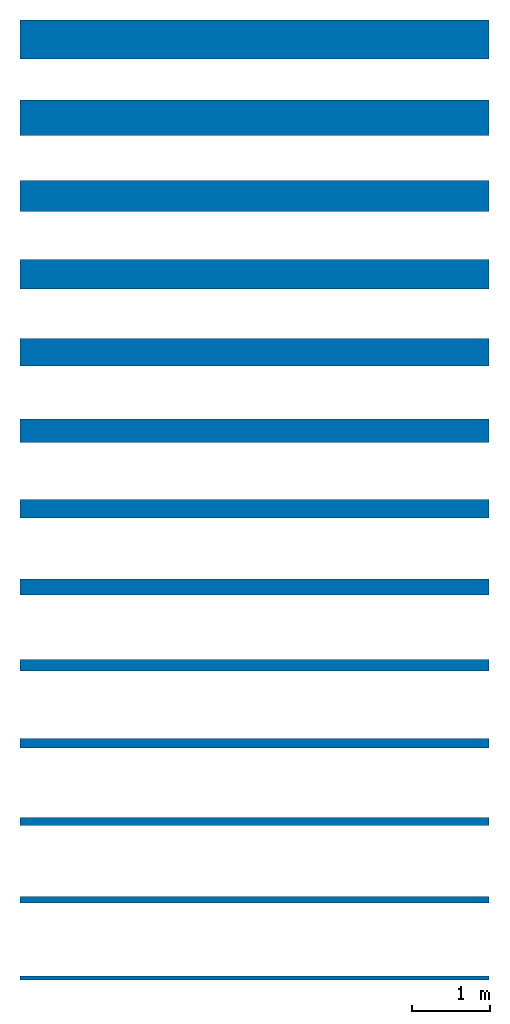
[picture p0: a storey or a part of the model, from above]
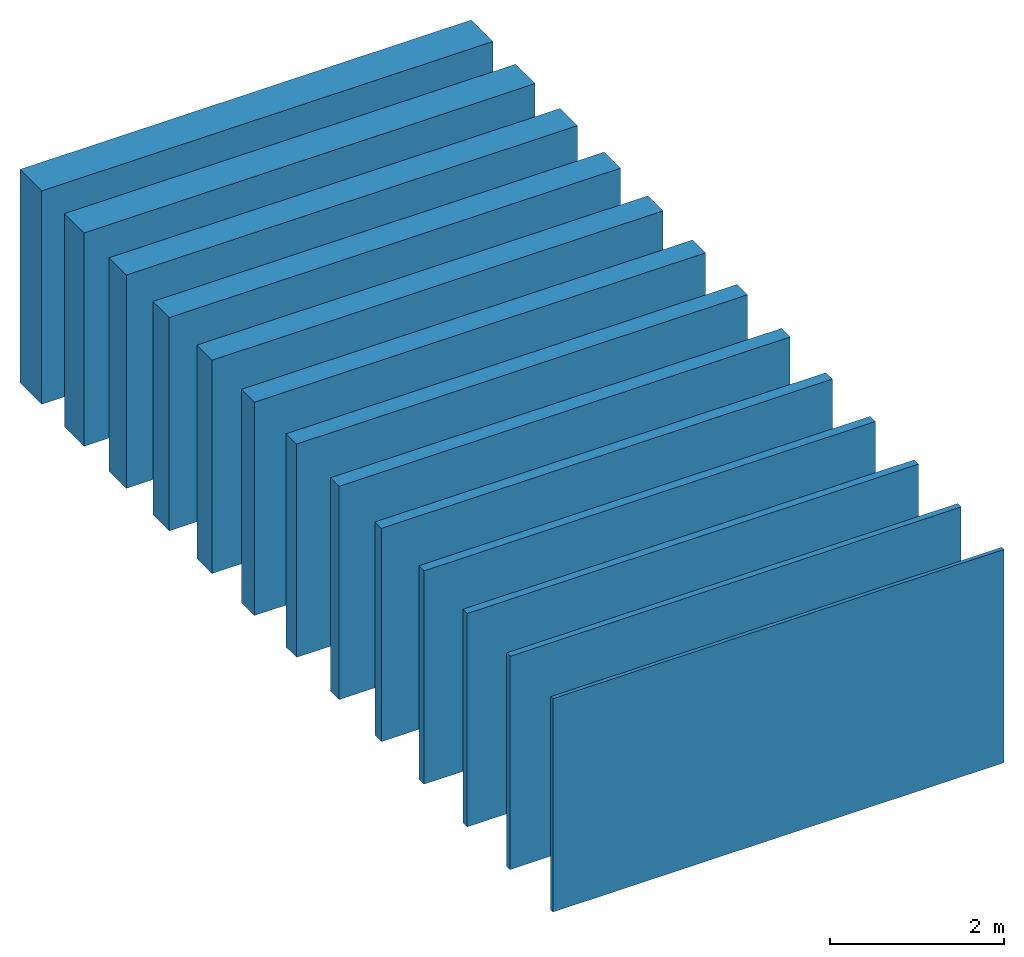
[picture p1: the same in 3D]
Properties of the parts of a building model (IFC2X3)

# File
Description: ViewDefinition [CoordinationView]
File name: Numero
Time: 2019-05-03T09:53:45
Written by: The EXPRESS Data Manager Version 5.02.0100.07 : 28 Aug 2013
Made in: 20150220_1215(x64) - Exporter 16.0.428.0 - Default UI
Comment: STEP Physical File produced by: The EXPRESS Data Manager Version 5.02.0100.07 : 28 Aug 2013 * Module: EDMstepFileFactory/EDMstandAlone * Creation date: Fri May 03 09:53:45 2019 * Host: HP-RS * Database: C:\Users\EKORU_~1\AppData\Local\Temp\{117FAC86-BFD7-4552-8663-6DD27C934700}\ifc * Database version: 5507 * Database creation date: Fri May 03 09:53:45 2019 * Schema: IFC2X3 * Model: DataRepository.ifc * Model creation date: Fri May 03 09:53:45 2019 * Header model: DataRepository.ifc_HeaderModel * Header model creation date: Fri May 03 09:53:45 2019 * EDMuser: sdai-user * EDMgroup: sdai-group * License ID and type: 5605 : Permanent license. Expiry date: * EDMstepFileFactory options: 020000

# IfcProject, Numero
LongName: Nome; Phase: Stato

# IfcSite, Default
RefLatitude: 41, 47, 59, 999999; RefLongitude: 12, 35, 59, 999999; RefElevation: 0 mm
Altro - Categoria: Informazioni sul progetto; Data di consegna del progetto: Data; Indirizzo del progetto: Immettere l'indirizzo; Nome del cliente: Proprietario; Nome del progetto: Nome; Numero del progetto: Numero; Stato del progetto: Stato

# IfcBuilding
Pset_BuildingCommon - NumberOfStoreys: 1
Altro - Categoria: Informazioni sul progetto; Data di consegna del progetto: Data; Indirizzo del progetto: Immettere l'indirizzo; Nome del cliente: Proprietario; Nome del progetto: Nome; Numero del progetto: Numero; Stato del progetto: Stato

# IfcBuildingStorey, Livello 1
LongName: Livello 1; Elevation: 0 mm
Vincoli - Base quota altimetrica: Punto base progetto; Quota altimetrica: 0 mm
Altro - Categoria: Livelli; Famiglia: Livello: Estremità 8 mm; Famiglia e tipo: Livello: Estremità 8 mm; ID tipo: Livello: Estremità 8 mm; Tipo: Livello: Estremità 8 mm; Nome famiglia: Livello
Dati identità - Strutturale: no; Nome: Livello 1; Piano edificio: yes; Nome del tipo: Estremità 8 mm
Dimensioni - Altezza di calcolo: 0 mm
Grafica - Colore: 0; Modello di linea: Centro; Simbolo: Estremità del livello - Cerchio: Estremità del livello - Cerchio; Simbolo a estremità 1 per default: no; Simbolo a estremità 2 per default: yes; Spessore di linea: 1

# IfcWallStandardCase: Muro di base:GASBETON Evolution sp. 100 mm, Muro di base:GASBETON Evolution sp. 100 mm:129163
In: Livello 1
Type - PredefinedType: STANDARD; Material: GASBETON Evolution 100 mm
Type - Altro - Categoria: Muri; Nome famiglia: Muro di base
Type - Costruzione - Funzione: Esterno; Ripiegatura agli inserti: Non ripiegare; Ripiegatura alle estremità: Nessuno; Larghezza: 100 mm
Type - Dati identità - Descrizione: muratura formata da blocchi GASBETON Evolution, densità a secco del singolo blocco 480 kg/mc; Installation Guide: http://www.gasbeton.it/wp-content/uploads/2017/11/GASBETON-Guida-alla-progettazione.pdf; Modello: Muratura Gasbeton Evolution; Nome del tipo: GASBETON Evolution sp. 100 mm; Product data url: https://www.bimobject.com/en/ekoru/product/gasbeton-evolution-basic; Produttore: EKORU s.r.l.; Resistenza al fuoco: EI 180; Euroclasse A1; Techinical data sheet: http://www.gasbeton.it/download/evolution/; URL: http://www.ekoru.it/; Youtube channel: https://www.youtube.com/user/bacchispa
Type - Generale - Edition number: 1; Manufacturer country: Italy; Manufacturer name: EKORU s.r.l.; Product family: walls
Type - Grafica - Colore del retino a dettaglio basso: 0
Type - Materiali e finiture - Materiale strutturale: GASBETON Evolution; Material main: Autoclaved Aerated Concrete (AAC)
Type - Proprietà analitiche - Ruvidità: 2; Assorbimento: 0.7; Coefficiente di scambio termico (U): 1.1; Massa termica: 48000; Resistenza termica (R): 0.909091
Altro - Famiglia: Muro di base: GASBETON Evolution sp. 100 mm; Famiglia e tipo: Muro di base: GASBETON Evolution sp. 100 mm; ID tipo: Muro di base: GASBETON Evolution sp. 100 mm; Tipo: Muro di base: GASBETON Evolution sp. 100 mm
Dimensioni - Area: 18 m2; Lunghezza: 6000 mm; Volume: 1.8 m3
Fasi - Fase di creazione: Fase 1
Strutturale - Attiva modello analitico: no; Strutturale: no; Utilizzo strutturale: Non portante
Vincoli - Delimita il locale: yes; Distanza estensione base: 0 mm; Distanza estensione superiore: 0 mm; La base è associata: no; La parte superiore è associata: no; Linea di ubicazione: Linea d'asse del muro; Offset base: 0 mm; Offset superiore: 0 mm; Relativo a massa: no; Vincolo di base: Livello: Livello 1; Vincolo parte superiore: Livello: Livello 2; Altezza non collegata: 3000 mm
Pset_WallCommon - LoadBearing: no; ExtendToStructure: no; IsExternal: yes; Reference: GASBETON Evolution sp. 100 mm; FireRating: EI 180; Euroclasse A1; ThermalTransmittance: 1.1 kg/K/s3
Pset_ManufacturerTypeInformation - Manufacturer: EKORU s.r.l.

# IfcWallStandardCase: Muro di base:GASBETON Evolution sp. 120 mm, Muro di base:GASBETON Evolution sp. 120 mm:129098
In: Livello 1
Type - PredefinedType: STANDARD; Material: GASBETON Evolution 120 mm
Type - Altro - Categoria: Muri; Nome famiglia: Muro di base
Type - Costruzione - Funzione: Esterno; Ripiegatura agli inserti: Non ripiegare; Ripiegatura alle estremità: Nessuno; Larghezza: 120 mm
Type - Dati identità - Descrizione: muratura formata da blocchi GASBETON Evolution, densità a secco del singolo blocco 480 kg/mc; Installation Guide: http://www.gasbeton.it/wp-content/uploads/2017/11/GASBETON-Guida-alla-progettazione.pdf; Modello: Muratura Gasbeton Evolution; Nome del tipo: GASBETON Evolution sp. 120 mm; Product data url: https://www.bimobject.com/en/ekoru/product/gasbeton-evolution-basic; Produttore: EKORU s.r.l.; Resistenza al fuoco: EI 180; Euroclasse A1; Techinical data sheet: http://www.gasbeton.it/download/evolution/; URL: http://www.ekoru.it/; Youtube channel: https://www.youtube.com/user/bacchispa
Type - Generale - Edition number: 1; Manufacturer country: Italy; Manufacturer name: EKORU s.r.l.; Product family: walls
Type - Grafica - Colore del retino a dettaglio basso: 0
Type - Materiali e finiture - Materiale strutturale: GASBETON Evolution; Material main: Autoclaved Aerated Concrete (AAC)
Type - Proprietà analitiche - Ruvidità: 2; Assorbimento: 0.7; Coefficiente di scambio termico (U): 0.916667; Massa termica: 57600; Resistenza termica (R): 1.09091
Altro - Famiglia: Muro di base: GASBETON Evolution sp. 120 mm; Famiglia e tipo: Muro di base: GASBETON Evolution sp. 120 mm; ID tipo: Muro di base: GASBETON Evolution sp. 120 mm; Tipo: Muro di base: GASBETON Evolution sp. 120 mm
Dimensioni - Area: 18 m2; Lunghezza: 6000 mm; Volume: 2.16 m3
Fasi - Fase di creazione: Fase 1
Strutturale - Attiva modello analitico: no; Strutturale: no; Utilizzo strutturale: Non portante
Vincoli - Delimita il locale: yes; Distanza estensione base: 0 mm; Distanza estensione superiore: 0 mm; La base è associata: no; La parte superiore è associata: no; Linea di ubicazione: Linea d'asse del muro; Offset base: 0 mm; Offset superiore: 0 mm; Relativo a massa: no; Vincolo di base: Livello: Livello 1; Vincolo parte superiore: Livello: Livello 2; Altezza non collegata: 3000 mm
Pset_WallCommon - LoadBearing: no; ExtendToStructure: no; IsExternal: yes; Reference: GASBETON Evolution sp. 120 mm; FireRating: EI 180; Euroclasse A1; ThermalTransmittance: 0.916667 kg/K/s3
Pset_ManufacturerTypeInformation - Manufacturer: EKORU s.r.l.

# IfcWallStandardCase: Muro di base:GASBETON Evolution sp. 150 mm, Muro di base:GASBETON Evolution sp. 150 mm:129011
In: Livello 1
Type - PredefinedType: STANDARD; Material: GASBETON Evolution 150 mm
Type - Altro - Categoria: Muri; Nome famiglia: Muro di base
Type - Costruzione - Funzione: Esterno; Ripiegatura agli inserti: Non ripiegare; Ripiegatura alle estremità: Nessuno; Larghezza: 150 mm
Type - Dati identità - Descrizione: muratura formata da blocchi GASBETON Evolution, densità a secco del singolo blocco 480 kg/mc; Installation Guide: http://www.gasbeton.it/wp-content/uploads/2017/11/GASBETON-Guida-alla-progettazione.pdf; Modello: Muratura Gasbeton Evolution; Nome del tipo: GASBETON Evolution sp. 150 mm; Product data url: www.gasbeton.it; Produttore: EKORU s.r.l.; Resistenza al fuoco: EI 180; Euroclasse A1; Techinical data sheet: http://www.gasbeton.it/download/evolution/; URL: http://www.ekoru.it/; Youtube channel: https://www.youtube.com/user/bacchispa
Type - Generale - Edition number: 1; Manufacturer country: Italy; Manufacturer name: EKORU s.r.l.; Product family: walls
Type - Grafica - Colore del retino a dettaglio basso: 0
Type - Materiali e finiture - Materiale strutturale: GASBETON Evolution; Material main: Autoclaved Aerated Concrete (AAC)
Type - Proprietà analitiche - Ruvidità: 2; Assorbimento: 0.7; Coefficiente di scambio termico (U): 0.733333; Massa termica: 72000; Resistenza termica (R): 1.36364
Altro - Famiglia: Muro di base: GASBETON Evolution sp. 150 mm; Famiglia e tipo: Muro di base: GASBETON Evolution sp. 150 mm; ID tipo: Muro di base: GASBETON Evolution sp. 150 mm; Tipo: Muro di base: GASBETON Evolution sp. 150 mm
Dimensioni - Area: 18 m2; Lunghezza: 6000 mm; Volume: 2.7 m3
Fasi - Fase di creazione: Fase 1
Strutturale - Attiva modello analitico: no; Strutturale: no; Utilizzo strutturale: Non portante
Vincoli - Delimita il locale: yes; Distanza estensione base: 0 mm; Distanza estensione superiore: 0 mm; La base è associata: no; La parte superiore è associata: no; Linea di ubicazione: Linea d'asse del muro; Offset base: 0 mm; Offset superiore: 0 mm; Relativo a massa: no; Vincolo di base: Livello: Livello 1; Vincolo parte superiore: Livello: Livello 2; Altezza non collegata: 3000 mm
Pset_WallCommon - LoadBearing: no; ExtendToStructure: no; IsExternal: yes; Reference: GASBETON Evolution sp. 150 mm; FireRating: EI 180; Euroclasse A1; ThermalTransmittance: 0.733333 kg/K/s3
Pset_ManufacturerTypeInformation - Manufacturer: EKORU s.r.l.

# IfcWallStandardCase: Muro di base:GASBETON Evolution sp. 200 mm, Muro di base:GASBETON Evolution sp. 200 mm:128937
In: Livello 1
Type - PredefinedType: STANDARD; Material: GASBETON Evolution 200 mm
Type - Altro - Categoria: Muri; Nome famiglia: Muro di base
Type - Costruzione - Funzione: Esterno; Ripiegatura agli inserti: Non ripiegare; Ripiegatura alle estremità: Nessuno; Larghezza: 200 mm
Type - Dati identità - Descrizione: muratura formata da blocchi GASBETON Evolution, densità a secco del singolo blocco 480 kg/mc; Installation Guide: http://www.gasbeton.it/wp-content/uploads/2017/11/GASBETON-Guida-alla-progettazione.pdf; Modello: Muratura Gasbeton Evolution; Nome del tipo: GASBETON Evolution sp. 200 mm; Product data url: https://www.bimobject.com/en/ekoru/product/gasbeton-evolution-basic; Produttore: EKORU s.r.l.; Resistenza al fuoco: EI 180; Euroclasse A1; Techinical data sheet: http://www.gasbeton.it/download/evolution/; URL: http://www.ekoru.it/; Youtube channel: https://www.youtube.com/user/bacchispa
Type - Generale - Edition number: 1; Manufacturer country: Italy; Manufacturer name: EKORU s.r.l.; Product family: walls
Type - Grafica - Colore del retino a dettaglio basso: 0
Type - Materiali e finiture - Materiale strutturale: GASBETON Evolution; Material main: Autoclaved Aerated Concrete (AAC)
Type - Proprietà analitiche - Ruvidità: 2; Assorbimento: 0.7; Coefficiente di scambio termico (U): 0.55; Massa termica: 96000; Resistenza termica (R): 1.81818
Altro - Famiglia: Muro di base: GASBETON Evolution sp. 200 mm; Famiglia e tipo: Muro di base: GASBETON Evolution sp. 200 mm; ID tipo: Muro di base: GASBETON Evolution sp. 200 mm; Tipo: Muro di base: GASBETON Evolution sp. 200 mm
Dimensioni - Area: 18 m2; Lunghezza: 6000 mm; Volume: 3.6 m3
Fasi - Fase di creazione: Fase 1
Strutturale - Attiva modello analitico: no; Strutturale: no; Utilizzo strutturale: Non portante
Vincoli - Delimita il locale: yes; Distanza estensione base: 0 mm; Distanza estensione superiore: 0 mm; La base è associata: no; La parte superiore è associata: no; Linea di ubicazione: Linea d'asse del muro; Offset base: 0 mm; Offset superiore: 0 mm; Relativo a massa: no; Vincolo di base: Livello: Livello 1; Vincolo parte superiore: Livello: Livello 2; Altezza non collegata: 3000 mm
Pset_WallCommon - LoadBearing: no; ExtendToStructure: no; IsExternal: yes; Reference: GASBETON Evolution sp. 200 mm; FireRating: EI 180; Euroclasse A1; ThermalTransmittance: 0.55 kg/K/s3
Pset_ManufacturerTypeInformation - Manufacturer: EKORU s.r.l.

# IfcWallStandardCase: Muro di base:GASBETON Evolution sp. 240 mm, Muro di base:GASBETON Evolution sp. 240 mm:128832
In: Livello 1
Type - PredefinedType: STANDARD; Material: GASBETON Evolution 240 mm
Type - Altro - Categoria: Muri; Nome famiglia: Muro di base
Type - Costruzione - Funzione: Esterno; Ripiegatura agli inserti: Non ripiegare; Ripiegatura alle estremità: Nessuno; Larghezza: 240 mm
Type - Dati identità - Descrizione: muratura formata da blocchi GASBETON Evolution, densità a secco del singolo blocco 480 kg/mc; Installation Guide: http://www.gasbeton.it/wp-content/uploads/2017/11/GASBETON-Guida-alla-progettazione.pdf; Modello: Muratura Gasbeton Evolution; Nome del tipo: GASBETON Evolution sp. 240 mm; Product data url: https://www.bimobject.com/en/ekoru/product/gasbeton-evolution-basic; Produttore: EKORU s.r.l.; Resistenza al fuoco: REI 180; EI 240; Euroclasse A1; Techinical data sheet: http://www.gasbeton.it/download/evolution/; URL: http://www.ekoru.it/; Youtube channel: https://www.youtube.com/user/bacchispa
Type - Generale - Edition number: 1; Manufacturer country: Italy; Manufacturer name: EKORU s.r.l.; Product family: walls
Type - Grafica - Colore del retino a dettaglio basso: 0
Type - Materiali e finiture - Materiale strutturale: GASBETON Evolution; Material main: Autoclaved Aerated Concrete (AAC)
Type - Proprietà analitiche - Ruvidità: 2; Assorbimento: 0.7; Coefficiente di scambio termico (U): 0.458333; Massa termica: 115200; Resistenza termica (R): 2.18182
Altro - Famiglia: Muro di base: GASBETON Evolution sp. 240 mm; Famiglia e tipo: Muro di base: GASBETON Evolution sp. 240 mm; ID tipo: Muro di base: GASBETON Evolution sp. 240 mm; Tipo: Muro di base: GASBETON Evolution sp. 240 mm
Dimensioni - Area: 18 m2; Lunghezza: 6000 mm; Volume: 4.32 m3
Fasi - Fase di creazione: Fase 1
Strutturale - Attiva modello analitico: no; Strutturale: no; Utilizzo strutturale: Non portante
Vincoli - Delimita il locale: yes; Distanza estensione base: 0 mm; Distanza estensione superiore: 0 mm; La base è associata: no; La parte superiore è associata: no; Linea di ubicazione: Linea d'asse del muro; Offset base: 0 mm; Offset superiore: 0 mm; Relativo a massa: no; Vincolo di base: Livello: Livello 1; Vincolo parte superiore: Livello: Livello 2; Altezza non collegata: 3000 mm
Pset_WallCommon - LoadBearing: no; ExtendToStructure: no; IsExternal: yes; Reference: GASBETON Evolution sp. 240 mm; FireRating: REI 180; EI 240; Euroclasse A1; ThermalTransmittance: 0.458333 kg/K/s3
Pset_ManufacturerTypeInformation - Manufacturer: EKORU s.r.l.

# IfcWallStandardCase: Muro di base:GASBETON Evolution sp. 300 mm, Muro di base:GASBETON Evolution sp. 300 mm:128767
In: Livello 1
Type - PredefinedType: STANDARD; Material: GASBETON Evolution 300 mm
Type - Altro - Categoria: Muri; Nome famiglia: Muro di base
Type - Costruzione - Funzione: Esterno; Ripiegatura agli inserti: Non ripiegare; Ripiegatura alle estremità: Nessuno; Larghezza: 300 mm
Type - Dati identità - Descrizione: muratura formata da blocchi GASBETON Evolution, densità a secco del singolo blocco 480 kg/mc; Installation Guide: http://www.gasbeton.it/wp-content/uploads/2017/11/GASBETON-Guida-alla-progettazione.pdf; Modello: Muratura Gasbeton Evolution; Nome del tipo: GASBETON Evolution sp. 300 mm; Product data url: https://www.bimobject.com/en/ekoru/product/gasbeton-evolution-basic; Produttore: EKORU s.r.l.; Resistenza al fuoco: REI 240; Euroclasse A1; Techinical data sheet: http://www.gasbeton.it/download/evolution/; URL: http://www.ekoru.it/; Youtube channel: https://www.youtube.com/user/bacchispa
Type - Generale - Edition number: 1; Manufacturer country: Italy; Manufacturer name: EKORU s.r.l.; Product family: walls
Type - Grafica - Colore del retino a dettaglio basso: 0
Type - Materiali e finiture - Materiale strutturale: GASBETON Evolution; Material main: Autoclaved Aerated Concrete (AAC)
Type - Proprietà analitiche - Ruvidità: 2; Assorbimento: 0.7; Coefficiente di scambio termico (U): 0.366667; Massa termica: 144000; Resistenza termica (R): 2.72727
Altro - Famiglia: Muro di base: GASBETON Evolution sp. 300 mm; Famiglia e tipo: Muro di base: GASBETON Evolution sp. 300 mm; ID tipo: Muro di base: GASBETON Evolution sp. 300 mm; Tipo: Muro di base: GASBETON Evolution sp. 300 mm
Dimensioni - Area: 18 m2; Lunghezza: 6000 mm; Volume: 5.4 m3
Fasi - Fase di creazione: Fase 1
Strutturale - Attiva modello analitico: no; Strutturale: no; Utilizzo strutturale: Non portante
Vincoli - Delimita il locale: yes; Distanza estensione base: 0 mm; Distanza estensione superiore: 0 mm; La base è associata: no; La parte superiore è associata: no; Linea di ubicazione: Linea d'asse del muro; Offset base: 0 mm; Offset superiore: 0 mm; Relativo a massa: no; Vincolo di base: Livello: Livello 1; Vincolo parte superiore: Livello: Livello 2; Altezza non collegata: 3000 mm
Pset_WallCommon - LoadBearing: no; ExtendToStructure: no; IsExternal: yes; Reference: GASBETON Evolution sp. 300 mm; FireRating: REI 240; Euroclasse A1; ThermalTransmittance: 0.366667 kg/K/s3
Pset_ManufacturerTypeInformation - Manufacturer: EKORU s.r.l.

# IfcWallStandardCase: Muro di base:GASBETON Evolution sp. 350 mm, Muro di base:GASBETON Evolution sp. 350 mm:128649
In: Livello 1
Type - PredefinedType: STANDARD; Material: GASBETON Evolution 350 mm
Type - Altro - Categoria: Muri; Nome famiglia: Muro di base
Type - Costruzione - Funzione: Esterno; Ripiegatura agli inserti: Non ripiegare; Ripiegatura alle estremità: Nessuno; Larghezza: 350 mm
Type - Dati identità - Descrizione: muratura formata da blocchi GASBETON Evolution, densità a secco del singolo blocco 480 kg/mc; Installation Guide: http://www.gasbeton.it/wp-content/uploads/2017/11/GASBETON-Guida-alla-progettazione.pdf; Modello: Muratura Gasbeton Evolution; Nome del tipo: GASBETON Evolution sp. 350 mm; Product data url: https://www.bimobject.com/en/ekoru/product/gasbeton-evolution-basic; Produttore: EKORU s.r.l.; Resistenza al fuoco: REI 240; Euroclasse A1; Techinical data sheet: http://www.gasbeton.it/download/evolution/; URL: http://www.ekoru.it/; Youtube channel: https://www.youtube.com/user/bacchispa
Type - Generale - Edition number: 1; Manufacturer country: Italy; Manufacturer name: EKORU s.r.l.; Product family: walls
Type - Grafica - Colore del retino a dettaglio basso: 0
Type - Materiali e finiture - Materiale strutturale: GASBETON Evolution; Material main: Autoclaved Aerated Concrete (AAC)
Type - Proprietà analitiche - Ruvidità: 2; Assorbimento: 0.7; Coefficiente di scambio termico (U): 0.314286; Massa termica: 168000; Resistenza termica (R): 3.18182
Altro - Famiglia: Muro di base: GASBETON Evolution sp. 350 mm; Famiglia e tipo: Muro di base: GASBETON Evolution sp. 350 mm; ID tipo: Muro di base: GASBETON Evolution sp. 350 mm; Tipo: Muro di base: GASBETON Evolution sp. 350 mm
Dimensioni - Area: 18 m2; Lunghezza: 6000 mm; Volume: 6.3 m3
Fasi - Fase di creazione: Fase 1
Strutturale - Attiva modello analitico: no; Strutturale: no; Utilizzo strutturale: Non portante
Vincoli - Delimita il locale: yes; Distanza estensione base: 0 mm; Distanza estensione superiore: 0 mm; La base è associata: no; La parte superiore è associata: no; Linea di ubicazione: Linea d'asse del muro; Offset base: 0 mm; Offset superiore: 0 mm; Relativo a massa: no; Vincolo di base: Livello: Livello 1; Vincolo parte superiore: Livello: Livello 2; Altezza non collegata: 3000 mm
Pset_WallCommon - LoadBearing: no; ExtendToStructure: no; IsExternal: yes; Reference: GASBETON Evolution sp. 350 mm; FireRating: REI 240; Euroclasse A1; ThermalTransmittance: 0.314286 kg/K/s3
Pset_ManufacturerTypeInformation - Manufacturer: EKORU s.r.l.

# IfcWallStandardCase: Muro di base:GASBETON Evolution sp. 375 mm, Muro di base:GASBETON Evolution sp. 375 mm:128584
In: Livello 1
Type - PredefinedType: STANDARD; Material: GASBETON Evolution 375 mm
Type - Altro - Categoria: Muri; Nome famiglia: Muro di base
Type - Costruzione - Funzione: Esterno; Ripiegatura agli inserti: Non ripiegare; Ripiegatura alle estremità: Nessuno; Larghezza: 375 mm
Type - Dati identità - Descrizione: muratura formata da blocchi GASBETON Evolution, densità a secco del singolo blocco 480 kg/mc; Installation Guide: http://www.gasbeton.it/wp-content/uploads/2017/11/GASBETON-Guida-alla-progettazione.pdf; Modello: Muratura Gasbeton Evolution; Nome del tipo: GASBETON Evolution sp. 375 mm; Product data url: https://www.bimobject.com/en/ekoru/product/gasbeton-evolution-basic; Produttore: EKORU s.r.l.; Resistenza al fuoco: REI 240; Euroclasse A1; Techinical data sheet: http://www.gasbeton.it/download/evolution/; URL: http://www.ekoru.it/; Youtube channel: https://www.youtube.com/user/bacchispa
Type - Generale - Edition number: 1; Manufacturer country: Italy; Manufacturer name: EKORU s.r.l.; Product family: walls
Type - Grafica - Colore del retino a dettaglio basso: 0
Type - Materiali e finiture - Materiale strutturale: GASBETON Evolution; Material main: Autoclaved Aerated Concrete (AAC)
Type - Proprietà analitiche - Ruvidità: 2; Assorbimento: 0.7; Coefficiente di scambio termico (U): 0.293333; Massa termica: 180000; Resistenza termica (R): 3.40909
Altro - Famiglia: Muro di base: GASBETON Evolution sp. 375 mm; Famiglia e tipo: Muro di base: GASBETON Evolution sp. 375 mm; ID tipo: Muro di base: GASBETON Evolution sp. 375 mm; Tipo: Muro di base: GASBETON Evolution sp. 375 mm
Dimensioni - Area: 18 m2; Lunghezza: 6000 mm; Volume: 6.75 m3
Fasi - Fase di creazione: Fase 1
Strutturale - Attiva modello analitico: no; Strutturale: no; Utilizzo strutturale: Non portante
Vincoli - Delimita il locale: yes; Distanza estensione base: 0 mm; Distanza estensione superiore: 0 mm; La base è associata: no; La parte superiore è associata: no; Linea di ubicazione: Linea d'asse del muro; Offset base: 0 mm; Offset superiore: 0 mm; Relativo a massa: no; Vincolo di base: Livello: Livello 1; Vincolo parte superiore: Livello: Livello 2; Altezza non collegata: 3000 mm
Pset_WallCommon - LoadBearing: no; ExtendToStructure: no; IsExternal: yes; Reference: GASBETON Evolution sp. 375 mm; FireRating: REI 240; Euroclasse A1; ThermalTransmittance: 0.293333 kg/K/s3
Pset_ManufacturerTypeInformation - Manufacturer: EKORU s.r.l.

# IfcWallStandardCase: Muro di base:GASBETON Evolution sp. 400 mm, Muro di base:GASBETON Evolution sp. 400 mm:128497
In: Livello 1
Type - PredefinedType: STANDARD; Material: GASBETON Evolution 400 mm
Type - Altro - Categoria: Muri; Nome famiglia: Muro di base
Type - Costruzione - Funzione: Esterno; Ripiegatura agli inserti: Non ripiegare; Ripiegatura alle estremità: Nessuno; Larghezza: 400 mm
Type - Dati identità - Descrizione: muratura formata da blocchi GASBETON Evolution, densità a secco del singolo blocco 480 kg/mc; Installation Guide: http://www.gasbeton.it/wp-content/uploads/2017/11/GASBETON-Guida-alla-progettazione.pdf; Modello: Muratura Gasbeton Evolution; Nome del tipo: GASBETON Evolution sp. 400 mm; Product data url: https://www.bimobject.com/en/ekoru/product/gasbeton-evolution-basic; Produttore: EKORU s.r.l.; Resistenza al fuoco: REI 240; Euroclasse A1; Techinical data sheet: http://www.gasbeton.it/download/evolution/; URL: http://www.ekoru.it/; Youtube channel: https://www.youtube.com/user/bacchispa
Type - Generale - Edition number: 1; Manufacturer country: Italy; Manufacturer name: EKORU s.r.l.; Product family: walls
Type - Grafica - Colore del retino a dettaglio basso: 0
Type - Materiali e finiture - Materiale strutturale: GASBETON Evolution; Material main: Autoclaved Aerated Concrete (AAC)
Type - Proprietà analitiche - Ruvidità: 2; Assorbimento: 0.7; Coefficiente di scambio termico (U): 0.275; Massa termica: 192000; Resistenza termica (R): 3.63636
Altro - Famiglia: Muro di base: GASBETON Evolution sp. 400 mm; Famiglia e tipo: Muro di base: GASBETON Evolution sp. 400 mm; ID tipo: Muro di base: GASBETON Evolution sp. 400 mm; Tipo: Muro di base: GASBETON Evolution sp. 400 mm
Dimensioni - Area: 18 m2; Lunghezza: 6000 mm; Volume: 7.2 m3
Fasi - Fase di creazione: Fase 1
Strutturale - Attiva modello analitico: no; Strutturale: no; Utilizzo strutturale: Non portante
Vincoli - Delimita il locale: yes; Distanza estensione base: 0 mm; Distanza estensione superiore: 0 mm; La base è associata: no; La parte superiore è associata: no; Linea di ubicazione: Linea d'asse del muro; Offset base: 0 mm; Offset superiore: 0 mm; Relativo a massa: no; Vincolo di base: Livello: Livello 1; Vincolo parte superiore: Livello: Livello 2; Altezza non collegata: 3000 mm
Pset_WallCommon - LoadBearing: no; ExtendToStructure: no; IsExternal: yes; Reference: GASBETON Evolution sp. 400 mm; FireRating: REI 240; Euroclasse A1; ThermalTransmittance: 0.275 kg/K/s3
Pset_ManufacturerTypeInformation - Manufacturer: EKORU s.r.l.

# IfcWallStandardCase: Muro di base:GASBETON Evolution sp. 450 mm, Muro di base:GASBETON Evolution sp. 450 mm:128387
In: Livello 1
Type - PredefinedType: STANDARD; Material: GASBETON Evolution 450 mm
Type - Altro - Categoria: Muri; Nome famiglia: Muro di base
Type - Costruzione - Funzione: Esterno; Ripiegatura agli inserti: Non ripiegare; Ripiegatura alle estremità: Nessuno; Larghezza: 450 mm
Type - Dati identità - Descrizione: muratura formata da blocchi GASBETON Evolution, densità a secco del singolo blocco 480 kg/mc; Installation Guide: http://www.gasbeton.it/wp-content/uploads/2017/11/GASBETON-Guida-alla-progettazione.pdf; Modello: Muratura Gasbeton Evolution; Nome del tipo: GASBETON Evolution sp. 450 mm; Product data url: https://www.bimobject.com/en/ekoru/product/gasbeton-evolution-basic; Produttore: EKORU s.r.l.; Resistenza al fuoco: REI 240; Euroclasse A1; Techinical data sheet: http://www.gasbeton.it/download/evolution/; URL: http://www.ekoru.it/; Youtube channel: https://www.youtube.com/user/bacchispa
Type - Generale - Edition number: 1; Manufacturer country: Italy; Manufacturer name: EKORU s.r.l.; Product family: walls
Type - Grafica - Colore del retino a dettaglio basso: 0
Type - Materiali e finiture - Materiale strutturale: GASBETON Evolution; Material main: Autoclaved Aerated Concrete (AAC)
Type - Proprietà analitiche - Ruvidità: 2; Assorbimento: 0.7; Coefficiente di scambio termico (U): 0.244444; Massa termica: 216000; Resistenza termica (R): 4.09091
Altro - Famiglia: Muro di base: GASBETON Evolution sp. 450 mm; Famiglia e tipo: Muro di base: GASBETON Evolution sp. 450 mm; ID tipo: Muro di base: GASBETON Evolution sp. 450 mm; Tipo: Muro di base: GASBETON Evolution sp. 450 mm
Dimensioni - Area: 18 m2; Lunghezza: 6000 mm; Volume: 8.1 m3
Fasi - Fase di creazione: Fase 1
Strutturale - Attiva modello analitico: no; Strutturale: no; Utilizzo strutturale: Non portante
Vincoli - Delimita il locale: yes; Distanza estensione base: 0 mm; Distanza estensione superiore: 0 mm; La base è associata: no; La parte superiore è associata: no; Linea di ubicazione: Linea d'asse del muro; Offset base: 0 mm; Offset superiore: 0 mm; Relativo a massa: no; Vincolo di base: Livello: Livello 1; Vincolo parte superiore: Livello: Livello 2; Altezza non collegata: 3000 mm
Pset_WallCommon - LoadBearing: no; ExtendToStructure: no; IsExternal: yes; Reference: GASBETON Evolution sp. 450 mm; FireRating: REI 240; Euroclasse A1; ThermalTransmittance: 0.244444 kg/K/s3
Pset_ManufacturerTypeInformation - Manufacturer: EKORU s.r.l.

# IfcWallStandardCase: Muro di base:GASBETON Evolution sp. 50 mm, Muro di base:GASBETON Evolution sp. 50 mm:129337
In: Livello 1
Type - PredefinedType: STANDARD; Material: GASBETON Evolution 50 mm
Type - Altro - Categoria: Muri; Nome famiglia: Muro di base
Type - Costruzione - Funzione: Esterno; Ripiegatura agli inserti: Non ripiegare; Ripiegatura alle estremità: Nessuno; Larghezza: 50 mm
Type - Dati identità - Descrizione: muratura formata da blocchi GASBETON Evolution, densità a secco del singolo blocco 480 kg/mc; Installation Guide: http://www.gasbeton.it/wp-content/uploads/2017/11/GASBETON-Guida-alla-progettazione.pdf; Modello: Muratura Gasbeton Evolution; Nome del tipo: GASBETON Evolution sp. 50 mm; Product data url: https://www.bimobject.com/en/ekoru/product/gasbeton-evolution-basic; Produttore: EKORU s.r.l.; Resistenza al fuoco: Euroclasse A1; Techinical data sheet: http://www.gasbeton.it/download/evolution/; URL: http://www.ekoru.it/; Youtube channel: https://www.youtube.com/user/bacchispa
Type - Generale - Edition number: 1; Manufacturer country: Italy; Manufacturer name: EKORU s.r.l.; Product family: walls
Type - Grafica - Colore del retino a dettaglio basso: 0
Type - Materiali e finiture - Materiale strutturale: GASBETON Evolution; Material main: Autoclaved Aerated Concrete (AAC)
Type - Proprietà analitiche - Ruvidità: 2; Assorbimento: 0.7; Coefficiente di scambio termico (U): 2.2; Massa termica: 24000; Resistenza termica (R): 0.454545
Altro - Famiglia: Muro di base: GASBETON Evolution sp. 50 mm; Famiglia e tipo: Muro di base: GASBETON Evolution sp. 50 mm; ID tipo: Muro di base: GASBETON Evolution sp. 50 mm; Tipo: Muro di base: GASBETON Evolution sp. 50 mm
Dimensioni - Area: 18 m2; Lunghezza: 6000 mm; Volume: 0.9 m3
Fasi - Fase di creazione: Fase 1
Strutturale - Attiva modello analitico: no; Strutturale: no; Utilizzo strutturale: Non portante
Vincoli - Delimita il locale: yes; Distanza estensione base: 0 mm; Distanza estensione superiore: 0 mm; La base è associata: no; La parte superiore è associata: no; Linea di ubicazione: Linea d'asse del muro; Offset base: 0 mm; Offset superiore: 0 mm; Relativo a massa: no; Vincolo di base: Livello: Livello 1; Vincolo parte superiore: Livello: Livello 2; Altezza non collegata: 3000 mm
Pset_WallCommon - LoadBearing: no; ExtendToStructure: no; IsExternal: yes; Reference: GASBETON Evolution sp. 50 mm; FireRating: Euroclasse A1; ThermalTransmittance: 2.2 kg/K/s3
Pset_ManufacturerTypeInformation - Manufacturer: EKORU s.r.l.

# IfcWallStandardCase: Muro di base:GASBETON Evolution sp. 500 mm, Muro di base:GASBETON Evolution sp. 500 mm:125781
In: Livello 1
Type - PredefinedType: STANDARD; Material: GASBETON Evolution 500 mm
Type - Altro - Categoria: Muri; Nome famiglia: Muro di base
Type - Costruzione - Funzione: Esterno; Larghezza: 500 mm; Ripiegatura agli inserti: Non ripiegare; Ripiegatura alle estremità: Nessuno
Type - Dati identità - Descrizione: muratura formata da blocchi GASBETON Evolution, densità a secco del singolo blocco 480 kg/mc; Installation Guide: http://www.gasbeton.it/wp-content/uploads/2017/11/GASBETON-Guida-alla-progettazione.pdf; Modello: Muratura Gasbeton Evolution; Nome del tipo: GASBETON Evolution sp. 500 mm; Product data url: www.gasbeton.it; Produttore: EKORU s.r.l.; Resistenza al fuoco: REI 240; Euroclasse A1; Techinical data sheet: http://www.gasbeton.it/download/evolution/; URL: http://www.ekoru.it/; Youtube channel: https://www.youtube.com/user/bacchispa
Type - Generale - Edition number: 1; Manufacturer country: Italy; Manufacturer name: EKORU s.r.l.; Product family: walls
Type - Grafica - Colore del retino a dettaglio basso: 0
Type - Materiali e finiture - Materiale strutturale: GASBETON Evolution; Material main: Autoclaved Aerated Concrete (AAC)
Type - Proprietà analitiche - Assorbimento: 0.7; Coefficiente di scambio termico (U): 0.22; Massa termica: 240000; Resistenza termica (R): 4.54545; Ruvidità: 2
Altro - Famiglia: Muro di base: GASBETON Evolution sp. 500 mm; Famiglia e tipo: Muro di base: GASBETON Evolution sp. 500 mm; ID tipo: Muro di base: GASBETON Evolution sp. 500 mm; Tipo: Muro di base: GASBETON Evolution sp. 500 mm
Dimensioni - Area: 18 m2; Lunghezza: 6000 mm; Volume: 9 m3
Fasi - Fase di creazione: Fase 1
Strutturale - Attiva modello analitico: no; Strutturale: no; Utilizzo strutturale: Non portante
Vincoli - Altezza non collegata: 3000 mm; Delimita il locale: yes; Distanza estensione base: 0 mm; Distanza estensione superiore: 0 mm; La base è associata: no; La parte superiore è associata: no; Linea di ubicazione: Linea d'asse del muro; Offset base: 0 mm; Offset superiore: 0 mm; Relativo a massa: no; Vincolo di base: Livello: Livello 1; Vincolo parte superiore: Livello: Livello 2
Pset_WallCommon - Reference: GASBETON Evolution sp. 500 mm; LoadBearing: no; ExtendToStructure: no; IsExternal: yes; FireRating: REI 240; Euroclasse A1; ThermalTransmittance: 0.22 kg/K/s3
Pset_ManufacturerTypeInformation - Manufacturer: EKORU s.r.l.

# IfcWallStandardCase: Muro di base:GASBETON Evolution sp. 80 mm, Muro di base:GASBETON Evolution sp. 80 mm:129263
In: Livello 1
Type - PredefinedType: STANDARD; Material: GASBETON Evolution 80 mm
Type - Altro - Categoria: Muri; Nome famiglia: Muro di base
Type - Costruzione - Funzione: Esterno; Ripiegatura agli inserti: Non ripiegare; Ripiegatura alle estremità: Nessuno; Larghezza: 80 mm
Type - Dati identità - Descrizione: muratura formata da blocchi GASBETON Evolution, densità a secco del singolo blocco 480 kg/mc; Installation Guide: http://www.gasbeton.it/wp-content/uploads/2017/11/GASBETON-Guida-alla-progettazione.pdf; Modello: Muratura Gasbeton Evolution; Nome del tipo: GASBETON Evolution sp. 80 mm; Product data url: www.gasbeton.it; Produttore: EKORU s.r.l.; Resistenza al fuoco: EI 120; Euroclasse A1; Techinical data sheet: http://www.gasbeton.it/download/evolution/; URL: http://www.ekoru.it/; Youtube channel: https://www.youtube.com/user/bacchispa
Type - Generale - Edition number: 1; Manufacturer country: Italy; Manufacturer name: EKORU s.r.l.; Product family: walls
Type - Grafica - Colore del retino a dettaglio basso: 0
Type - Materiali e finiture - Materiale strutturale: GASBETON Evolution; Material main: Autoclaved Aerated Concrete (AAC)
Type - Proprietà analitiche - Ruvidità: 2; Assorbimento: 0.7; Coefficiente di scambio termico (U): 1.375; Massa termica: 38400; Resistenza termica (R): 0.727273
Altro - Famiglia: Muro di base: GASBETON Evolution sp. 80 mm; Famiglia e tipo: Muro di base: GASBETON Evolution sp. 80 mm; ID tipo: Muro di base: GASBETON Evolution sp. 80 mm; Tipo: Muro di base: GASBETON Evolution sp. 80 mm
Dimensioni - Area: 18 m2; Lunghezza: 6000 mm; Volume: 1.44 m3
Fasi - Fase di creazione: Fase 1
Strutturale - Attiva modello analitico: no; Strutturale: no; Utilizzo strutturale: Non portante
Vincoli - Delimita il locale: yes; Distanza estensione base: 0 mm; Distanza estensione superiore: 0 mm; La base è associata: no; La parte superiore è associata: no; Linea di ubicazione: Linea d'asse del muro; Offset base: 0 mm; Offset superiore: 0 mm; Relativo a massa: no; Vincolo di base: Livello: Livello 1; Vincolo parte superiore: Livello: Livello 2; Altezza non collegata: 3000 mm
Pset_WallCommon - LoadBearing: no; ExtendToStructure: no; IsExternal: yes; Reference: GASBETON Evolution sp. 80 mm; FireRating: EI 120; Euroclasse A1; ThermalTransmittance: 1.375 kg/K/s3
Pset_ManufacturerTypeInformation - Manufacturer: EKORU s.r.l.
